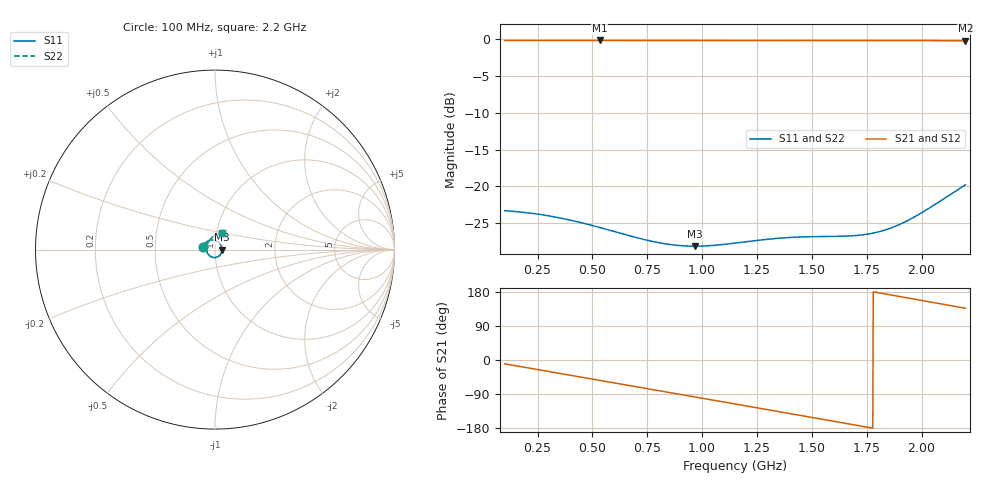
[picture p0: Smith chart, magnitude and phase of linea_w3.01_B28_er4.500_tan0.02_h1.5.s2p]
! Chirptenna · simulación 3D de una microstrip de dos puertos (S12 = S21, S22 = S11 por simetría)
# HZ S RI R 50
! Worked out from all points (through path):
!   1101 points, 100 MHz to 2.2 GHz, reference 50 ohm
!   highest |S21| = -0.15 dB at 533.4 MHz (marker M1); lowest = -0.2 dB at 2.2 GHz (marker M2)
!   group delay of S21, straight-line fit = 282 ps
!   lowest |S11| = -28.1 dB at 966.7 MHz (marker M3), VSWR 1.08, Z = 54.1 - j0.119 ohm
!   |S11| at or under -10 dB: start of sweep to end of sweep
!   |S22| runs from -28.1 to -19.8 dB; largest |S21 - S12| = 0
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1e8  -0.0663 0.0169  0.9676 -0.1717  0.9676 -0.1717  -0.0663 0.0169
1.820909e8  -0.0596 0.0297  0.9329 -0.3089  0.9329 -0.3089  -0.0596 0.0297
2.699091e8  -0.0494 0.041  0.8744 -0.4485  0.8744 -0.4485  -0.0494 0.041
3.596364e8  -0.0358 0.0489  0.7932 -0.5802  0.7932 -0.5802  -0.0358 0.0489
4.512727e8  -0.0202 0.0528  0.6899 -0.7  0.6899 -0.7  -0.0202 0.0528
5.333636e8  -0.0057 0.0522  0.5821 -0.792  0.5821 -0.792  -0.0057 0.0522
6.689091e8  0.0164 0.0432  0.3784 -0.907  0.3784 -0.907  0.0164 0.0432
8.006364e8  0.032 0.0263  0.1597 -0.9696  0.1597 -0.9696  0.032 0.0263
8.846364e8  0.0376 0.0128  0.0149 -0.9824  0.0149 -0.9824  0.0376 0.0128
9.667273e8  0.0392 -0.0011  -0.127 -0.9741  -0.127 -0.9741  0.0392 -0.0011
1.058364e9  0.0363 -0.0162  -0.2821 -0.9407  -0.2821 -0.9407  0.0363 -0.0162
1.15e9  0.0288 -0.0294  -0.4298 -0.8828  -0.4298 -0.8828  0.0288 -0.0294
1.318e9  0.00587 -0.0436  -0.6691 -0.7182  -0.6691 -0.7182  0.00587 -0.0436
1.411545e9  -0.00952 -0.044  -0.7783 -0.598  -0.7783 -0.598  -0.00952 -0.044
1.501273e9  -0.0239 -0.0387  -0.8633 -0.4671  -0.8633 -0.4671  -0.0239 -0.0387
1.591e9  -0.0362 -0.0279  -0.9265 -0.3241  -0.9265 -0.3241  -0.0362 -0.0279
1.678818e9  -0.0443 -0.0125  -0.9657 -0.1758  -0.9657 -0.1758  -0.0443 -0.0125
1.764727e9  -0.0472 0.00607  -0.9812 -0.026  -0.9812 -0.026  -0.0472 0.00607
1.850636e9  -0.0439 0.0268  -0.9734 0.1247  -0.9734 0.1247  -0.0439 0.0268
1.934636e9  -0.034 0.0474  -0.9432 0.2697  -0.9432 0.2697  -0.034 0.0474
2.018636e9  -0.0171 0.0665  -0.8911 0.4087  -0.8911 0.4087  -0.0171 0.0665
2.2e9  0.0415 0.0936  -0.7092 0.6724  -0.7092 0.6724  0.0415 0.0936
